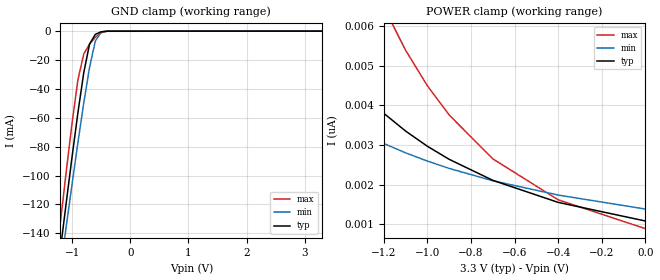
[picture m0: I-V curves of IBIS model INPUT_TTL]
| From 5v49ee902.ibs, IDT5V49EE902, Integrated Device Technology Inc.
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|   Model INPUT_TTL
[Model]   INPUT_TTL
Model_type   Input
Polarity   Non-Inverting
Vinl =  0.80000V
Vinh =  2.00000V
C_comp   3.15000pF   3.15000pF   3.15000pF
[Temperature Range]   25.00000   100.00000   -40.00000
[Voltage Range]   3.30000V   3.00000V   3.60000V
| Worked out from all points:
|   GND clamp passes 1 mA (typ) near -0.53 V on its own axis
[GND_clamp]
| voltage   I(typ)   I(min)   I(max)
-3.3V     -860.5mA   -813.9mA   -910.1mA
-1.3V     -183.6mA   -194.8mA   -167.8mA
-1.2V     -150.9mA   -164.8mA   -132.1mA
-1.1V     -118.6mA   -135.1mA   -97.13mA
-1V       -86.99mA   -105.9mA   -63.61mA
-900mV    -56.64mA   -77.31mA   -33.82mA
-800mV    -29.01mA   -50mA      -15.89mA
-700mV    -9.031mA   -25.22mA   -9.146mA
-600mV    -2.261mA   -6.881mA   -4.277mA
-500mV    -493.9uA   -650.7uA   -1.144mA
-400mV    -59.34uA   -43.85uA   -131.5uA
3.3V      1.08nA     1.636nA    591.5pA
[POWER_clamp]
| voltage   I(typ)   I(min)   I(max)
-3.3V     74.3nA     29.42nA    315.2nA
-1.9V     9.867nA    5.868nA    24.24nA
-1.6V     6.467nA    4.338nA    13.72nA
-1.5V     5.639nA    3.947nA    11.36nA
-1.4V     4.929nA    3.604nA    9.41nA
-1.2V     3.799nA    3.036nA    6.48nA
-1.1V     3.351nA    2.801nA    5.39nA
-1V       2.967nA    2.593nA    4.494nA
-900mV    2.637nA    2.408nA    3.756nA
-700mV    2.107nA    2.096nA    2.649nA
-400mV    1.55nA     1.735nA    1.615nA
0V        1.08nA     1.382nA    886.8pA
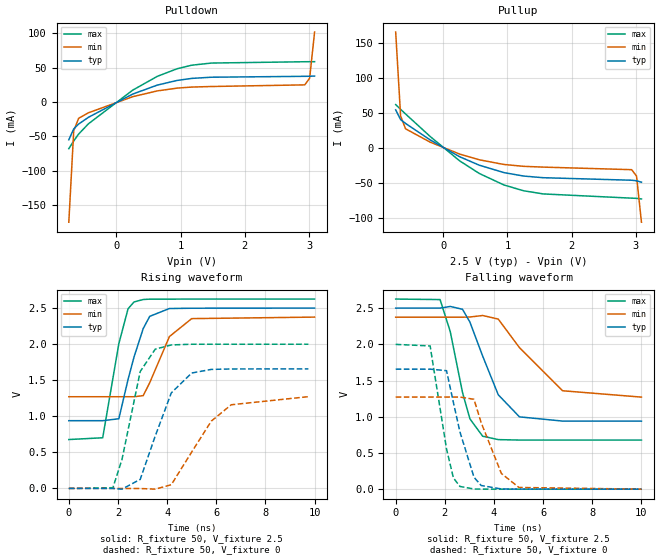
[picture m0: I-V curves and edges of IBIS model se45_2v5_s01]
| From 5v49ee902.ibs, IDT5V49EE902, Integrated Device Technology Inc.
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[Model]   se45_2v5_s01
Model_type   Output
Polarity   Non-Inverting
|   typ   min   max
C_comp   2pF   1.5pF   2.5pF
Vmeas = 1.25V
Rref = 50
Cref = 0
Vref = 1.25V
|   typ   min   max
[Voltage range]   2.5V   2.375V   2.625V
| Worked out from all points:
|   slope of the pulldown table from 0 to 0.375 V, typ, clamps not added: 23.2 ohm
|   slope of the pullup table from 0 to 0.375 V, typ, clamps not added: 21 ohm
|   rising waveform, R_fixture 50, V_fixture 2.5: 20-80 % time 748ps typ, 875ps min, 623ps max; typ from 0.939 V to 2.5 V
|   falling waveform, R_fixture 50, V_fixture 2.5: 20-80 % time 1.1ns typ, 1.47ns min, 751ps max; typ from 2.5 V to 0.939 V
|   rising waveform, R_fixture 50, V_fixture 0: 20-80 % time 1.03ns typ, 1.46ns min, 725ps max; typ from 0 V to 1.66 V
|   falling waveform, R_fixture 50, V_fixture 0: 20-80 % time 712ps typ, 832ps min, 579ps max; typ from 1.66 V to 0 V
[Pulldown]
|Voltage   I (typ)   I (min)   I (max)
|Note, modeling breaks down at 250mA and above.  This is well beyond the functional   |
|operating range of the device.  Should this scenario occur, catastrophic failure and   |
|possible damage to the device and/or board is of higher concern than the I-V curve   |
|behavior.  The IBIS checker will flag currents in excess of 10A with warnings.  Lines   |
|with currents in excess of 0.35 A have been commented out.  The points still remain|
|available to the user if the user desires to use them.   |
|-2.50000e+00   -4.54709e+01   -3.63694e+01   -6.07959e+01
|-2.42347e+00   -4.32502e+01   -3.46594e+01   -5.77053e+01
|-2.34694e+00   -4.10314e+01   -3.29511e+01   -5.46170e+01
|-2.27041e+00   -3.88148e+01   -3.12446e+01   -5.15313e+01
|-2.19388e+00   -3.66007e+01   -2.95401e+01   -4.84486e+01
|-2.11735e+00   -3.43893e+01   -2.78380e+01   -4.53691e+01
|-2.04082e+00   -3.21809e+01   -2.61384e+01   -4.22934e+01
|-1.96429e+00   -2.99761e+01   -2.44418e+01   -3.92219e+01
|-1.88776e+00   -2.77753e+01   -2.27484e+01   -3.61555e+01
|-1.81122e+00   -2.55791e+01   -2.10589e+01   -3.30948e+01
|-1.73469e+00   -2.33884e+01   -1.93737e+01   -3.00411e+01
|-1.65816e+00   -2.12042e+01   -1.76937e+01   -2.69958e+01
|-1.58163e+00   -1.90279e+01   -1.60198e+01   -2.39607e+01
|-1.50510e+00   -1.68611e+01   -1.43533e+01   -2.09385e+01
|-1.42857e+00   -1.47065e+01   -1.26960e+01   -1.79331e+01
|-1.35204e+00   -1.25675e+01   -1.10500e+01   -1.49501e+01
|-1.27551e+00   -1.04495e+01   -9.41889e+00   -1.19989e+01
|-1.19898e+00   -8.36102e+00   -7.80755e+00   -9.09553e+00
|-1.12245e+00   -6.31683e+00   -6.22400e+00   -6.27207e+00
|-1.04592e+00   -4.34540e+00   -4.68188e+00   -3.60463e+00
|-9.69388e-01   -2.51112e+00   -3.20700e+00   -1.33260e+00
|-8.92857e-01   -9.89892e-01   -1.85502e+00   -2.01598e-01
|-8.16327e-01   -1.92135e-01   -7.61074e-01   -8.24374e-02
-739.8mV  -54.82mA   -174.4mA   -67.73mA
-663.3mV  -39mA      -41.68mA   -56.5mA
-586.7mV  -31.96mA   -23.62mA   -46.47mA
-433.7mV  -22.15mA   -15.6mA    -31.55mA
255.1mV   11.54mA    7.746mA    17.23mA
637.8mV   24.55mA    16.14mA    37.26mA
943.9mV   31.29mA    20.16mA    48.22mA
1.173V    34.28mA    21.72mA    53.44mA
1.48V     36mA       22.52mA    56.56mA
2.934V    37.31mA    24.91mA    58.47mA
3.01V     37.39mA    34.58mA    58.51mA
3.087V    37.69mA    101.5mA    58.57mA
| 3.16327e+00   3.94370e-02   3.90716e-01   5.87161e-02
| 3.23980e+00   5.34569e-02   9.26332e-01   5.92247e-02
| 3.31633e+00   1.87777e-01   1.58664e+00   6.05142e-02
| 3.39286e+00   7.03900e-01   2.30650e+00   6.31621e-02
| 3.46939e+00   1.49296e+00   3.05902e+00   8.17834e-02
| 3.54592e+00   2.39302e+00   3.83167e+00   3.62573e-01
| 3.62245e+00   3.34512e+00   4.61786e+00   1.23067e+00
| 3.69898e+00   4.32630e+00   5.41369e+00   2.35283e+00
| 3.77551e+00   5.32579e+00   6.21672e+00   3.56536e+00
| 3.85204e+00   6.33779e+00   7.02533e+00   4.82080e+00
| 3.92857e+00   7.35883e+00   7.83838e+00   6.10084e+00
| 4.00510e+00   8.38670e+00   8.65504e+00   7.39669e+00
| 4.08163e+00   9.41993e+00   9.47469e+00   8.70352e+00
| 4.15816e+00   1.04574e+01   1.02969e+01   1.00184e+01
| 4.23469e+00   1.14984e+01   1.11212e+01   1.13394e+01
| 4.31122e+00   1.25424e+01   1.19474e+01   1.26653e+01
| 4.38776e+00   1.35888e+01   1.27751e+01   1.39952e+01
| 4.46429e+00   1.46373e+01   1.36044e+01   1.53282e+01
| 4.54082e+00   1.56877e+01   1.44348e+01   1.66640e+01
| 4.61735e+00   1.67397e+01   1.52665e+01   1.80021e+01
| 4.69388e+00   1.77932e+01   1.60991e+01   1.93422e+01
| 4.77041e+00   1.88479e+01   1.69326e+01   2.06841e+01
| 4.84694e+00   1.99037e+01   1.77670e+01   2.20275e+01
| 4.92347e+00   2.09606e+01   1.86021e+01   2.33723e+01
| 5.00000e+00   2.20184e+01   1.94379e+01   2.47183e+01
[Pullup]
|Voltage   I (typ)   I (min)   I (max)
|Note, modeling breaks down at 250mA and above.  This is well beyond the functional   |
|operating range of the device.  Should this scenario occur, catastrophic failure and   |
|possible damage to the device and/or board is of higher concern than the I-V curve   |
|behavior.  The IBIS checker will flag currents in excess of 10A with warnings.  Lines   |
|with currents in excess of 0.35 A have been commented out.  The points still remain|
|available to the user if the user desires to use them.   |
|-2.50000e+00   2.19765e+01   1.80472e+01   2.68517e+01
|-2.42347e+00   2.09191e+01   1.72127e+01   2.55048e+01
|-2.34694e+00   1.98626e+01   1.63791e+01   2.41589e+01
|-2.27041e+00   1.88071e+01   1.55463e+01   2.28141e+01
|-2.19388e+00   1.77528e+01   1.47145e+01   2.14705e+01
|-2.11735e+00   1.66997e+01   1.38838e+01   2.01283e+01
|-2.04082e+00   1.56480e+01   1.30543e+01   1.87877e+01
|-1.96429e+00   1.45980e+01   1.22261e+01   1.74489e+01
|-1.88776e+00   1.35497e+01   1.13995e+01   1.61122e+01
|-1.81122e+00   1.25036e+01   1.05747e+01   1.47780e+01
|-1.73469e+00   1.14600e+01   9.75186e+00   1.34466e+01
|-1.65816e+00   1.04193e+01   8.93142e+00   1.21187e+01
|-1.58163e+00   9.38215e+00   8.11380e+00   1.07950e+01
|-1.50510e+00   8.34928e+00   7.29955e+00   9.47668e+00
|-1.42857e+00   7.32178e+00   6.48942e+00   8.16516e+00
|-1.35204e+00   6.30119e+00   5.68442e+00   6.86272e+00
|-1.27551e+00   5.28973e+00   4.88602e+00   5.57292e+00
|-1.19898e+00   4.29091e+00   4.09630e+00   4.30185e+00
|-1.12245e+00   3.31066e+00   3.31857e+00   3.06117e+00
|-1.04592e+00   2.36002e+00   2.55827e+00   1.87712e+00
|-9.69388e-01   1.46263e+00   1.82537e+00   8.26238e-01
|-8.92857e-01   6.79721e-01   1.14025e+00   1.77022e-01
|-8.16327e-01   1.78304e-01   5.50947e-01   7.20287e-02
-739.8mV  54.64mA    166.3mA    62.19mA
-663.3mV  40.61mA    45.96mA    55.4mA
-586.7mV  35.13mA    27.42mA    48.78mA
-204.1mV  11.53mA    8.292mA    16.47mA
255.1mV   -12.67mA   -8.857mA   -18.54mA
561.2mV   -24.84mA   -17.08mA   -36.7mA
943.9mV   -35.45mA   -23.78mA   -53.18mA
1.25V     -40.42mA   -26.48mA   -61.53mA
1.556V    -42.81mA   -27.59mA   -66.09mA
2.934V    -46.44mA   -31.28mA   -72.19mA
3.01V     -47.21mA   -40.39mA   -72.48mA
3.087V    -49.28mA   -106.7mA   -73.28mA
| 3.16327e+00   -5.35776e-02   -4.94236e-01   -7.58575e-02
| 3.23980e+00   -6.85824e-02   -1.43626e+00   -8.09811e-02
| 3.31633e+00   -2.12479e-01   -2.71822e+00   -8.81300e-02
| 3.39286e+00   -1.02359e+00   -4.15794e+00   -9.69442e-02
| 3.46939e+00   -2.55073e+00   -5.67974e+00   -1.18777e-01
| 3.54592e+00   -4.38708e+00   -7.25021e+00   -4.69271e-01
| 3.62245e+00   -6.35927e+00   -8.85247e+00   -2.14689e+00
| 3.69898e+00   -8.40369e+00   -1.04769e+01   -4.62063e+00
| 3.77551e+00   -1.04921e+01   -1.21177e+01   -7.36117e+00
| 3.85204e+00   -1.26099e+01   -1.37710e+01   -1.02197e+01
| 3.92857e+00   -1.47486e+01   -1.54342e+01   -1.31429e+01
| 4.00510e+00   -1.69029e+01   -1.71053e+01   -1.61066e+01
| 4.08163e+00   -1.90692e+01   -1.87829e+01   -1.90980e+01
| 4.15816e+00   -2.12452e+01   -2.04660e+01   -2.21093e+01
| 4.23469e+00   -2.34289e+01   -2.21537e+01   -2.51357e+01
| 4.31122e+00   -2.56192e+01   -2.38455e+01   -2.81738e+01
| 4.38776e+00   -2.78148e+01   -2.55407e+01   -3.12215e+01
| 4.46429e+00   -3.00151e+01   -2.72389e+01   -3.42769e+01
| 4.54082e+00   -3.22195e+01   -2.89399e+01   -3.73388e+01
| 4.61735e+00   -3.44273e+01   -3.06432e+01   -4.04061e+01
| 4.69388e+00   -3.66382e+01   -3.23486e+01   -4.34782e+01
| 4.77041e+00   -3.88519e+01   -3.40560e+01   -4.65543e+01
| 4.84694e+00   -4.10679e+01   -3.57652e+01   -4.96340e+01
| 4.92347e+00   -4.32862e+01   -3.74759e+01   -5.27168e+01
| 5.00000e+00   -4.55064e+01   -3.91880e+01   -5.58024e+01
[Ramp]
|   typ   min   max
dV/dt_r   0.936/0.747n   0.662/0.874n   1.168/0.623n
dV/dt_f   0.951/1.109n   0.676/1.496n   1.186/0.762n
R_load =   50
[Rising Waveform]
R_fixture = 50
V_fixture = 2.5   |Vcc_typ
V_fixture_min = 2.375 |Vcc_min
V_fixture_max = 2.625 |Vcc_max
C_fixture = 0.0p
| Time   typ   min   max
0s        939.3mV    1.271V     677.7mV
1.379ns   939.3mV    1.271V     702.4mV
2.035ns   965.7mV    1.271V     2.006V
2.411ns   1.511V     1.271V     2.491V
2.654ns   1.823V     1.271V     2.585V
3.027ns   2.216V     1.286V     2.619V
3.293ns   2.386V     1.466V     2.624V
4.095ns   2.494V     2.106V     2.624V
5ns       2.498V     2.354V     2.625V
10ns      2.5V       2.375V     2.625V
[Falling Waveform]
R_fixture = 50
V_fixture = 2.5   |Vcc_typ
V_fixture_min = 2.375 |Vcc_min
V_fixture_max = 2.625 |Vcc_max
C_fixture = 0.0p
| Time   typ   min   max
0s        2.5V       2.375V     2.625V
1.806ns   2.5V       2.375V     2.618V
2.22ns    2.523V     2.375V     2.176V
2.718ns   2.484V     2.375V     1.336V
3.019ns   2.308V     2.377V     971.7mV
3.538ns   1.839V     2.398V     731.3mV
4.172ns   1.304V     2.349V     684.3mV
5.036ns   998.4mV    1.954V     678.1mV
6.789ns   940.3mV    1.359V     677.8mV
10ns      939.4mV    1.271V     677.8mV
[Rising Waveform]
R_fixture = 50
V_fixture = 0
C_fixture = 0.0p
| Time   typ   min   max
0s        96.64nV    102.5nV    85.59nV
1.795ns   -48.57uV   108.9nV    10.23mV
2.163ns   -10.07mV   7.207nV    401.4mV
2.905ns   125.5mV    -1.052mV   1.621V
3.518ns   727.9mV    -10.15mV   1.931V
4.171ns   1.325V     52.09mV    1.989V
5ns       1.6V       504.9mV    1.999V
5.799ns   1.65V      933.5mV    1.999V
6.608ns   1.656V     1.16V      1.999V
9.748ns   1.657V     1.272V     1.999V
[Falling Waveform]
R_fixture = 50
V_fixture = 0
C_fixture = 0.0p
| Time   typ   min   max
0s        1.657V     1.272V     1.999V
1.401ns   1.657V     1.272V     1.978V
2.069ns   1.636V     1.272V     554.6mV
2.348ns   1.197V     1.272V     155.5mV
2.614ns   790.9mV    1.272V     37.82mV
3.185ns   165.4mV    1.241V     2.015mV
3.478ns   50.48mV    918.2mV    1.131mV
4.3ns     2.689mV    217.2mV    261.2uV
5.013ns   752.7uV    23.58mV    110.6uV
10ns      69.28uV    129.6uV    37.48uV
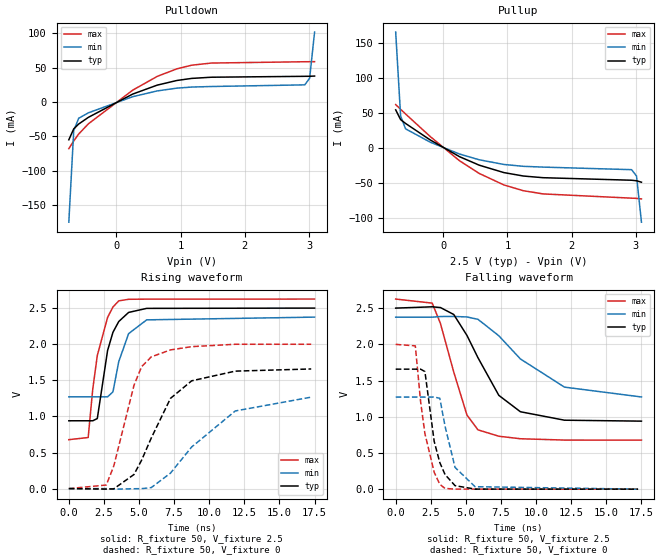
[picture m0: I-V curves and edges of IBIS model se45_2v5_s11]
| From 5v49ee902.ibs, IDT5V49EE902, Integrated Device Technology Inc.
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[Model]   se45_2v5_s11
Model_type   Output
Polarity   Non-Inverting
|   typ   min   max
C_comp   2pF   1.5pF   2.5pF
Vmeas = 1.25V
Rref = 50
Cref = 0
Vref = 1.25V
|   typ   min   max
[Voltage range]   2.5V   2.375V   2.625V
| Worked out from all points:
|   slope of the pulldown table from 0 to 0.375 V, typ, clamps not added: 23.2 ohm
|   slope of the pullup table from 0 to 0.375 V, typ, clamps not added: 21 ohm
|   rising waveform, R_fixture 50, V_fixture 2.5: 20-80 % time 963ps typ, 986ps min, 954ps max; typ from 0.939 V to 2.5 V
|   falling waveform, R_fixture 50, V_fixture 2.5: 20-80 % time 2.63ns typ, 3.79ns min, 1.72ns max; typ from 2.5 V to 0.939 V
|   rising waveform, R_fixture 50, V_fixture 0: 20-80 % time 2.5ns typ, 3.77ns min, 1.64ns max; typ from 0 V to 1.66 V
|   falling waveform, R_fixture 50, V_fixture 0: 20-80 % time 935ps typ, 945ps min, 910ps max; typ from 1.66 V to 0 V
[Pulldown]
|Voltage   I (typ)   I (min)   I (max)
|Note, modeling breaks down at 250mA and above.  This is well beyond the functional   |
|operating range of the device.  Should this scenario occur, catastrophic failure and   |
|possible damage to the device and/or board is of higher concern than the I-V curve   |
|behavior.  The IBIS checker will flag currents in excess of 10A with warnings.  Lines   |
|with currents in excess of 0.35 A have been commented out.  The points still remain|
|available to the user if the user desires to use them.   |
|-2.50000e+00   -4.54709e+01   -3.63694e+01   -6.07959e+01
|-2.42347e+00   -4.32502e+01   -3.46594e+01   -5.77053e+01
|-2.34694e+00   -4.10314e+01   -3.29511e+01   -5.46170e+01
|-2.27041e+00   -3.88148e+01   -3.12446e+01   -5.15313e+01
|-2.19388e+00   -3.66007e+01   -2.95401e+01   -4.84486e+01
|-2.11735e+00   -3.43893e+01   -2.78380e+01   -4.53691e+01
|-2.04082e+00   -3.21809e+01   -2.61384e+01   -4.22934e+01
|-1.96429e+00   -2.99761e+01   -2.44418e+01   -3.92219e+01
|-1.88776e+00   -2.77753e+01   -2.27484e+01   -3.61555e+01
|-1.81122e+00   -2.55791e+01   -2.10589e+01   -3.30948e+01
|-1.73469e+00   -2.33884e+01   -1.93737e+01   -3.00411e+01
|-1.65816e+00   -2.12042e+01   -1.76937e+01   -2.69958e+01
|-1.58163e+00   -1.90279e+01   -1.60198e+01   -2.39607e+01
|-1.50510e+00   -1.68611e+01   -1.43533e+01   -2.09385e+01
|-1.42857e+00   -1.47065e+01   -1.26960e+01   -1.79331e+01
|-1.35204e+00   -1.25675e+01   -1.10500e+01   -1.49501e+01
|-1.27551e+00   -1.04495e+01   -9.41889e+00   -1.19989e+01
|-1.19898e+00   -8.36102e+00   -7.80755e+00   -9.09553e+00
|-1.12245e+00   -6.31683e+00   -6.22400e+00   -6.27207e+00
|-1.04592e+00   -4.34540e+00   -4.68188e+00   -3.60463e+00
|-9.69388e-01   -2.51112e+00   -3.20700e+00   -1.33260e+00
|-8.92857e-01   -9.89892e-01   -1.85502e+00   -2.01598e-01
|-8.16327e-01   -1.92135e-01   -7.61074e-01   -8.24374e-02
-739.8mV  -54.82mA   -174.4mA   -67.73mA
-663.3mV  -39mA      -41.68mA   -56.5mA
-586.7mV  -31.96mA   -23.62mA   -46.47mA
-433.7mV  -22.15mA   -15.6mA    -31.55mA
255.1mV   11.54mA    7.746mA    17.23mA
637.8mV   24.55mA    16.14mA    37.26mA
943.9mV   31.29mA    20.16mA    48.22mA
1.173V    34.28mA    21.72mA    53.44mA
1.48V     36mA       22.52mA    56.56mA
2.934V    37.31mA    24.91mA    58.47mA
3.01V     37.39mA    34.58mA    58.51mA
3.087V    37.69mA    101.5mA    58.57mA
| 3.16327e+00   3.94370e-02   3.90716e-01   5.87161e-02
| 3.23980e+00   5.34569e-02   9.26332e-01   5.92247e-02
| 3.31633e+00   1.87777e-01   1.58664e+00   6.05142e-02
| 3.39286e+00   7.03900e-01   2.30650e+00   6.31621e-02
| 3.46939e+00   1.49296e+00   3.05902e+00   8.17834e-02
| 3.54592e+00   2.39302e+00   3.83167e+00   3.62573e-01
| 3.62245e+00   3.34512e+00   4.61786e+00   1.23067e+00
| 3.69898e+00   4.32630e+00   5.41369e+00   2.35283e+00
| 3.77551e+00   5.32579e+00   6.21672e+00   3.56536e+00
| 3.85204e+00   6.33779e+00   7.02533e+00   4.82080e+00
| 3.92857e+00   7.35883e+00   7.83838e+00   6.10084e+00
| 4.00510e+00   8.38670e+00   8.65504e+00   7.39669e+00
| 4.08163e+00   9.41993e+00   9.47469e+00   8.70352e+00
| 4.15816e+00   1.04574e+01   1.02969e+01   1.00184e+01
| 4.23469e+00   1.14984e+01   1.11212e+01   1.13394e+01
| 4.31122e+00   1.25424e+01   1.19474e+01   1.26653e+01
| 4.38776e+00   1.35888e+01   1.27751e+01   1.39952e+01
| 4.46429e+00   1.46373e+01   1.36044e+01   1.53282e+01
| 4.54082e+00   1.56877e+01   1.44348e+01   1.66640e+01
| 4.61735e+00   1.67397e+01   1.52665e+01   1.80021e+01
| 4.69388e+00   1.77932e+01   1.60991e+01   1.93422e+01
| 4.77041e+00   1.88479e+01   1.69326e+01   2.06841e+01
| 4.84694e+00   1.99037e+01   1.77670e+01   2.20275e+01
| 4.92347e+00   2.09606e+01   1.86021e+01   2.33723e+01
| 5.00000e+00   2.20184e+01   1.94379e+01   2.47183e+01
[Pullup]
|Voltage   I (typ)   I (min)   I (max)
|Note, modeling breaks down at 250mA and above.  This is well beyond the functional   |
|operating range of the device.  Should this scenario occur, catastrophic failure and   |
|possible damage to the device and/or board is of higher concern than the I-V curve   |
|behavior.  The IBIS checker will flag currents in excess of 10A with warnings.  Lines   |
|with currents in excess of 0.35 A have been commented out.  The points still remain|
|available to the user if the user desires to use them.   |
|-2.50000e+00   2.19765e+01   1.80472e+01   2.68517e+01
|-2.42347e+00   2.09191e+01   1.72127e+01   2.55048e+01
|-2.34694e+00   1.98626e+01   1.63791e+01   2.41589e+01
|-2.27041e+00   1.88071e+01   1.55463e+01   2.28141e+01
|-2.19388e+00   1.77528e+01   1.47145e+01   2.14705e+01
|-2.11735e+00   1.66997e+01   1.38838e+01   2.01283e+01
|-2.04082e+00   1.56480e+01   1.30543e+01   1.87877e+01
|-1.96429e+00   1.45980e+01   1.22261e+01   1.74489e+01
|-1.88776e+00   1.35497e+01   1.13995e+01   1.61122e+01
|-1.81122e+00   1.25036e+01   1.05747e+01   1.47780e+01
|-1.73469e+00   1.14600e+01   9.75186e+00   1.34466e+01
|-1.65816e+00   1.04193e+01   8.93142e+00   1.21187e+01
|-1.58163e+00   9.38215e+00   8.11380e+00   1.07950e+01
|-1.50510e+00   8.34928e+00   7.29955e+00   9.47668e+00
|-1.42857e+00   7.32178e+00   6.48942e+00   8.16516e+00
|-1.35204e+00   6.30119e+00   5.68442e+00   6.86272e+00
|-1.27551e+00   5.28973e+00   4.88602e+00   5.57292e+00
|-1.19898e+00   4.29091e+00   4.09630e+00   4.30185e+00
|-1.12245e+00   3.31066e+00   3.31857e+00   3.06117e+00
|-1.04592e+00   2.36002e+00   2.55827e+00   1.87712e+00
|-9.69388e-01   1.46263e+00   1.82537e+00   8.26238e-01
|-8.92857e-01   6.79721e-01   1.14025e+00   1.77022e-01
|-8.16327e-01   1.78304e-01   5.50947e-01   7.20287e-02
-739.8mV  54.64mA    166.3mA    62.19mA
-663.3mV  40.61mA    45.96mA    55.4mA
-586.7mV  35.13mA    27.42mA    48.78mA
-204.1mV  11.53mA    8.292mA    16.47mA
255.1mV   -12.67mA   -8.857mA   -18.54mA
561.2mV   -24.84mA   -17.08mA   -36.7mA
943.9mV   -35.45mA   -23.78mA   -53.18mA
1.25V     -40.42mA   -26.48mA   -61.53mA
1.556V    -42.81mA   -27.59mA   -66.09mA
2.934V    -46.44mA   -31.28mA   -72.19mA
3.01V     -47.21mA   -40.39mA   -72.48mA
3.087V    -49.28mA   -106.7mA   -73.28mA
| 3.16327e+00   -5.35776e-02   -4.94236e-01   -7.58575e-02
| 3.23980e+00   -6.85824e-02   -1.43626e+00   -8.09811e-02
| 3.31633e+00   -2.12479e-01   -2.71822e+00   -8.81300e-02
| 3.39286e+00   -1.02359e+00   -4.15794e+00   -9.69442e-02
| 3.46939e+00   -2.55073e+00   -5.67974e+00   -1.18777e-01
| 3.54592e+00   -4.38708e+00   -7.25021e+00   -4.69271e-01
| 3.62245e+00   -6.35927e+00   -8.85247e+00   -2.14689e+00
| 3.69898e+00   -8.40369e+00   -1.04769e+01   -4.62063e+00
| 3.77551e+00   -1.04921e+01   -1.21177e+01   -7.36117e+00
| 3.85204e+00   -1.26099e+01   -1.37710e+01   -1.02197e+01
| 3.92857e+00   -1.47486e+01   -1.54342e+01   -1.31429e+01
| 4.00510e+00   -1.69029e+01   -1.71053e+01   -1.61066e+01
| 4.08163e+00   -1.90692e+01   -1.87829e+01   -1.90980e+01
| 4.15816e+00   -2.12452e+01   -2.04660e+01   -2.21093e+01
| 4.23469e+00   -2.34289e+01   -2.21537e+01   -2.51357e+01
| 4.31122e+00   -2.56192e+01   -2.38455e+01   -2.81738e+01
| 4.38776e+00   -2.78148e+01   -2.55407e+01   -3.12215e+01
| 4.46429e+00   -3.00151e+01   -2.72389e+01   -3.42769e+01
| 4.54082e+00   -3.22195e+01   -2.89399e+01   -3.73388e+01
| 4.61735e+00   -3.44273e+01   -3.06432e+01   -4.04061e+01
| 4.69388e+00   -3.66382e+01   -3.23486e+01   -4.34782e+01
| 4.77041e+00   -3.88519e+01   -3.40560e+01   -4.65543e+01
| 4.84694e+00   -4.10679e+01   -3.57652e+01   -4.96340e+01
| 4.92347e+00   -4.32862e+01   -3.74759e+01   -5.27168e+01
| 5.00000e+00   -4.55064e+01   -3.91880e+01   -5.58024e+01
[Ramp]
|   typ   min   max
dV/dt_r   0.936/0.963n   0.662/0.986n   1.168/0.953n
dV/dt_f   0.951/2.67n  0.675/3.841n   1.186/1.745n
R_load =   50
[Rising Waveform]
R_fixture = 50
V_fixture = 2.5   |Vcc_typ
V_fixture_min = 2.375 |Vcc_min
V_fixture_max = 2.625 |Vcc_max
C_fixture = 0.0p
| Time   typ   min   max
0s        939.3mV    1.271V     677.7mV
1.379ns   939.3mV    1.271V     707.5mV
1.705ns   939.3mV    1.271V     1.379V
2.029ns   970.5mV    1.271V     1.844V
2.76ns    1.912V     1.271V     2.37V
3.143ns   2.165V     1.34V      2.515V
3.556ns   2.314V     1.759V     2.6V
4.258ns   2.44V      2.146V     2.622V
5.544ns   2.496V     2.337V     2.624V
17.5ns    2.5V       2.375V     2.625V
[Falling Waveform]
R_fixture = 50
V_fixture = 2.5   |Vcc_typ
V_fixture_min = 2.375 |Vcc_min
V_fixture_max = 2.625 |Vcc_max
C_fixture = 0.0p
| Time   typ   min   max
0s        2.5V       2.375V     2.625V
2.6ns     2.518V     2.375V     2.569V
3.186ns   2.508V     2.384V     2.288V
4.133ns   2.412V     2.385V     1.618V
5.074ns   2.123V     2.378V     1.023V
5.861ns   1.814V     2.345V     818.9mV
7.345ns   1.295V     2.118V     730.9mV
8.881ns   1.069V     1.798V     696.2mV
12.02ns   952.3mV    1.409V     677.9mV
17.5ns    939.3mV    1.273V     677.7mV
[Rising Waveform]
R_fixture = 50
V_fixture = 0
C_fixture = 0.0p
| Time   typ   min   max
0s        96.64nV    102.5nV    85.59nV
2.668ns   -7.256mV   32.44uV    49.65mV
3.199ns   -3.215mV   -7.738mV   311.5mV
4.638ns   195.2mV    -1.95mV    1.429V
5.18ns    392.6mV    -822.5uV   1.688V
5.875ns   702.1mV    14.3mV     1.825V
7.241ns   1.25V      215mV      1.921V
8.75ns    1.493V     576.9mV    1.966V
11.85ns   1.627V     1.075V     1.999V
17.26ns   1.657V     1.267V     1.999V
[Falling Waveform]
R_fixture = 50
V_fixture = 0
C_fixture = 0.0p
| Time   typ   min   max
0s        1.657V     1.272V     1.999V
1.397ns   1.657V     1.272V     1.979V
1.774ns   1.657V     1.272V     1.208V
2.081ns   1.624V     1.272V     767.4mV
2.742ns   659mV      1.272V     232.8mV
3.141ns   367.5mV    1.255V     66.94mV
3.515ns   201.4mV    868.7mV    9.915mV
4.227ns   48.27mV    300.1mV    1.079mV
5.65ns    1.231mV    34.22mV    461.5uV
17.26ns   31.51uV    67.45uV    18.41uV
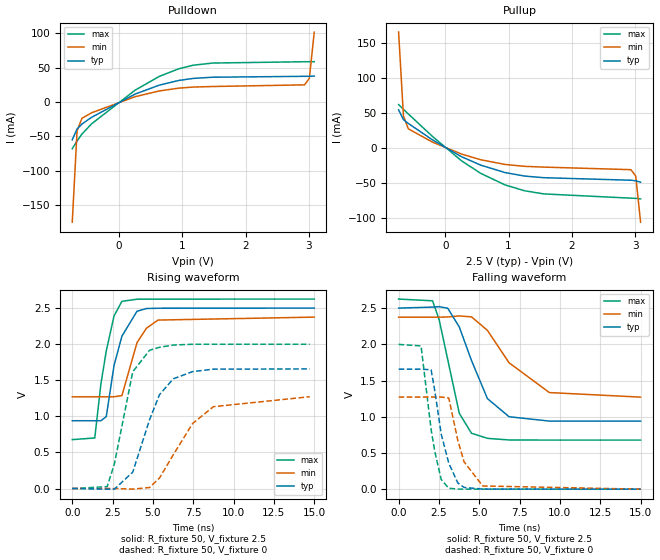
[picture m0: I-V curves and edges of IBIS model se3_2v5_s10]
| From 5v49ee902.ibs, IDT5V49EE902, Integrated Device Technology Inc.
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[Model]   se3_2v5_s10
Model_type   Output
Polarity   Non-Inverting
|   typ   min   max
C_comp   2pF   1.5pF   2.5pF
Vmeas = 1.25V
Rref = 50
Cref = 0
Vref = 1.25V
|   typ   min   max
[Voltage range]   2.5V   2.375V   2.625V
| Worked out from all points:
|   slope of the pulldown table from 0 to 0.375 V, typ, clamps not added: 23.2 ohm
|   slope of the pullup table from 0 to 0.375 V, typ, clamps not added: 21 ohm
|   rising waveform, R_fixture 50, V_fixture 2.5: 20-80 % time 951ps typ, 993ps min, 848ps max; typ from 0.939 V to 2.5 V
|   falling waveform, R_fixture 50, V_fixture 2.5: 20-80 % time 1.64ns typ, 2.29ns min, 1.11ns max; typ from 2.5 V to 0.939 V
|   rising waveform, R_fixture 50, V_fixture 0: 20-80 % time 1.55ns typ, 2.25ns min, 1.06ns max; typ from 0 V to 1.66 V
|   falling waveform, R_fixture 50, V_fixture 0: 20-80 % time 888ps typ, 940ps min, 786ps max; typ from 1.66 V to 0 V
[Pulldown]
|Voltage   I (typ)   I (min)   I (max)
|Note, modeling breaks down at 250mA and above.  This is well beyond the functional   |
|operating range of the device.  Should this scenario occur, catastrophic failure and   |
|possible damage to the device and/or board is of higher concern than the I-V curve   |
|behavior.  The IBIS checker will flag currents in excess of 10A with warnings.  Lines   |
|with currents in excess of 0.35 A have been commented out.  The points still remain|
|available to the user if the user desires to use them.   |
|-2.50000e+00   -4.54709e+01   -3.63694e+01   -6.07959e+01
|-2.42347e+00   -4.32502e+01   -3.46594e+01   -5.77053e+01
|-2.34694e+00   -4.10314e+01   -3.29511e+01   -5.46170e+01
|-2.27041e+00   -3.88148e+01   -3.12446e+01   -5.15313e+01
|-2.19388e+00   -3.66007e+01   -2.95401e+01   -4.84486e+01
|-2.11735e+00   -3.43893e+01   -2.78380e+01   -4.53691e+01
|-2.04082e+00   -3.21809e+01   -2.61384e+01   -4.22934e+01
|-1.96429e+00   -2.99761e+01   -2.44418e+01   -3.92219e+01
|-1.88776e+00   -2.77753e+01   -2.27484e+01   -3.61555e+01
|-1.81122e+00   -2.55791e+01   -2.10589e+01   -3.30948e+01
|-1.73469e+00   -2.33884e+01   -1.93737e+01   -3.00411e+01
|-1.65816e+00   -2.12042e+01   -1.76937e+01   -2.69958e+01
|-1.58163e+00   -1.90279e+01   -1.60198e+01   -2.39607e+01
|-1.50510e+00   -1.68611e+01   -1.43533e+01   -2.09385e+01
|-1.42857e+00   -1.47065e+01   -1.26960e+01   -1.79331e+01
|-1.35204e+00   -1.25675e+01   -1.10500e+01   -1.49501e+01
|-1.27551e+00   -1.04495e+01   -9.41889e+00   -1.19989e+01
|-1.19898e+00   -8.36102e+00   -7.80755e+00   -9.09553e+00
|-1.12245e+00   -6.31683e+00   -6.22400e+00   -6.27207e+00
|-1.04592e+00   -4.34540e+00   -4.68188e+00   -3.60463e+00
|-9.69388e-01   -2.51112e+00   -3.20700e+00   -1.33260e+00
|-8.92857e-01   -9.89892e-01   -1.85502e+00   -2.01598e-01
|-8.16327e-01   -1.92135e-01   -7.61074e-01   -8.24374e-02
-739.8mV  -54.82mA   -174.4mA   -67.73mA
-663.3mV  -39mA      -41.68mA   -56.5mA
-586.7mV  -31.96mA   -23.62mA   -46.47mA
-433.7mV  -22.15mA   -15.6mA    -31.55mA
255.1mV   11.54mA    7.746mA    17.23mA
637.8mV   24.55mA    16.14mA    37.26mA
943.9mV   31.29mA    20.16mA    48.22mA
1.173V    34.28mA    21.72mA    53.44mA
1.48V     36mA       22.52mA    56.56mA
2.934V    37.31mA    24.91mA    58.47mA
3.01V     37.39mA    34.58mA    58.51mA
3.087V    37.69mA    101.5mA    58.57mA
| 3.16327e+00   3.94370e-02   3.90706e-01   5.87161e-02
| 3.23980e+00   5.34568e-02   9.26296e-01   5.92247e-02
| 3.31633e+00   1.87774e-01   1.58657e+00   6.05142e-02
| 3.39286e+00   7.03870e-01   2.30639e+00   6.31621e-02
| 3.46939e+00   1.49288e+00   3.05886e+00   8.17834e-02
| 3.54592e+00   2.39288e+00   3.83148e+00   3.62561e-01
| 3.62245e+00   3.34491e+00   4.61762e+00   1.23059e+00
| 3.69898e+00   4.32602e+00   5.41341e+00   2.35266e+00
| 3.77551e+00   5.32544e+00   6.21640e+00   3.56507e+00
| 3.85204e+00   6.33737e+00   7.02496e+00   4.82041e+00
| 3.92857e+00   7.35834e+00   7.83797e+00   6.10033e+00
| 4.00510e+00   8.38614e+00   8.65458e+00   7.39607e+00
| 4.08163e+00   9.41929e+00   9.47419e+00   8.70278e+00
| 4.15816e+00   1.04567e+01   1.02963e+01   1.00176e+01
| 4.23469e+00   1.14977e+01   1.11206e+01   1.13385e+01
| 4.31122e+00   1.25415e+01   1.19467e+01   1.26642e+01
| 4.38776e+00   1.35879e+01   1.27745e+01   1.39940e+01
| 4.46429e+00   1.46363e+01   1.36036e+01   1.53269e+01
| 4.54082e+00   1.56867e+01   1.44341e+01   1.66626e+01
| 4.61735e+00   1.67386e+01   1.52656e+01   1.80006e+01
| 4.69388e+00   1.77920e+01   1.60982e+01   1.93406e+01
| 4.77041e+00   1.88466e+01   1.69317e+01   2.06823e+01
| 4.84694e+00   1.99024e+01   1.77660e+01   2.20256e+01
| 4.92347e+00   2.09592e+01   1.86011e+01   2.33703e+01
| 5.00000e+00   2.20169e+01   1.94369e+01   2.47161e+01
[Pullup]
|Voltage   I (typ)   I (min)   I (max)
|Note, modeling breaks down at 250mA and above.  This is well beyond the functional   |
|operating range of the device.  Should this scenario occur, catastrophic failure and   |
|possible damage to the device and/or board is of higher concern than the I-V curve   |
|behavior.  The IBIS checker will flag currents in excess of 10A with warnings.  Lines   |
|with currents in excess of 0.35 A have been commented out.  The points still remain|
|available to the user if the user desires to use them.   |
|-2.50000e+00   2.19749e+01   1.80462e+01   2.68494e+01
|-2.42347e+00   2.09176e+01   1.72118e+01   2.55026e+01
|-2.34694e+00   1.98612e+01   1.63782e+01   2.41568e+01
|-2.27041e+00   1.88058e+01   1.55455e+01   2.28121e+01
|-2.19388e+00   1.77516e+01   1.47137e+01   2.14686e+01
|-2.11735e+00   1.66986e+01   1.38831e+01   2.01266e+01
|-2.04082e+00   1.56470e+01   1.30536e+01   1.87861e+01
|-1.96429e+00   1.45970e+01   1.22255e+01   1.74474e+01
|-1.88776e+00   1.35488e+01   1.13989e+01   1.61108e+01
|-1.81122e+00   1.25028e+01   1.05741e+01   1.47767e+01
|-1.73469e+00   1.14592e+01   9.75133e+00   1.34454e+01
|-1.65816e+00   1.04186e+01   8.93094e+00   1.21176e+01
|-1.58163e+00   9.38151e+00   8.11336e+00   1.07941e+01
|-1.50510e+00   8.34872e+00   7.29916e+00   9.47586e+00
|-1.42857e+00   7.32129e+00   6.48907e+00   8.16447e+00
|-1.35204e+00   6.30078e+00   5.68413e+00   6.86214e+00
|-1.27551e+00   5.28938e+00   4.88577e+00   5.57245e+00
|-1.19898e+00   4.29063e+00   4.09609e+00   4.30150e+00
|-1.12245e+00   3.31046e+00   3.31840e+00   3.06092e+00
|-1.04592e+00   2.35988e+00   2.55815e+00   1.87698e+00
|-9.69388e-01   1.46255e+00   1.82528e+00   8.26188e-01
|-8.92857e-01   6.79691e-01   1.14020e+00   1.77018e-01
|-8.16327e-01   1.78301e-01   5.50929e-01   7.20286e-02
-739.8mV  54.64mA    166.3mA    62.19mA
-663.3mV  40.61mA    45.96mA    55.4mA
-586.7mV  35.13mA    27.42mA    48.78mA
-204.1mV  11.53mA    8.292mA    16.47mA
255.1mV   -12.67mA   -8.857mA   -18.54mA
561.2mV   -24.84mA   -17.08mA   -36.7mA
943.9mV   -35.45mA   -23.78mA   -53.18mA
1.25V     -40.42mA   -26.48mA   -61.53mA
1.556V    -42.81mA   -27.59mA   -66.09mA
2.934V    -46.44mA   -31.28mA   -72.19mA
3.01V     -47.21mA   -40.39mA   -72.48mA
3.087V    -49.28mA   -106.7mA   -73.28mA
| 3.16327e+00   -5.35776e-02   -4.94236e-01   -7.58575e-02
| 3.23980e+00   -6.85824e-02   -1.43626e+00   -8.09810e-02
| 3.31633e+00   -2.12479e-01   -2.71822e+00   -8.81300e-02
| 3.39286e+00   -1.02359e+00   -4.15794e+00   -9.69441e-02
| 3.46939e+00   -2.55073e+00   -5.67974e+00   -1.18777e-01
| 3.54592e+00   -4.38708e+00   -7.25021e+00   -4.69271e-01
| 3.62245e+00   -6.35927e+00   -8.85247e+00   -2.14689e+00
| 3.69898e+00   -8.40369e+00   -1.04769e+01   -4.62063e+00
| 3.77551e+00   -1.04921e+01   -1.21177e+01   -7.36117e+00
| 3.85204e+00   -1.26099e+01   -1.37710e+01   -1.02197e+01
| 3.92857e+00   -1.47486e+01   -1.54342e+01   -1.31429e+01
| 4.00510e+00   -1.69029e+01   -1.71053e+01   -1.61066e+01
| 4.08163e+00   -1.90692e+01   -1.87829e+01   -1.90980e+01
| 4.15816e+00   -2.12452e+01   -2.04660e+01   -2.21093e+01
| 4.23469e+00   -2.34289e+01   -2.21537e+01   -2.51357e+01
| 4.31122e+00   -2.56192e+01   -2.38455e+01   -2.81738e+01
| 4.38776e+00   -2.78148e+01   -2.55407e+01   -3.12215e+01
| 4.46429e+00   -3.00151e+01   -2.72389e+01   -3.42769e+01
| 4.54082e+00   -3.22195e+01   -2.89399e+01   -3.73388e+01
| 4.61735e+00   -3.44273e+01   -3.06432e+01   -4.04061e+01
| 4.69388e+00   -3.66382e+01   -3.23486e+01   -4.34782e+01
| 4.77041e+00   -3.88519e+01   -3.40560e+01   -4.65543e+01
| 4.84694e+00   -4.10679e+01   -3.57652e+01   -4.96340e+01
| 4.92347e+00   -4.32862e+01   -3.74759e+01   -5.27168e+01
| 5.00000e+00   -4.55064e+01   -3.91880e+01   -5.58024e+01
[Ramp]
|   typ   min   max
dV/dt_r   0.936/0.951n   0.662/0.993n   1.168/0.848n
dV/dt_f   0.952/1.669n   0.676/2.324n   1.185/1.124n
R_load =   50
[Rising Waveform]
R_fixture = 50
V_fixture = 2.5   |Vcc_typ
V_fixture_min = 2.375 |Vcc_min
V_fixture_max = 2.625 |Vcc_max
C_fixture = 0.0p
| Time   typ   min   max
0s        939.3mV    1.271V     677.7mV
1.396ns   939.3mV    1.271V     700.7mV
1.774ns   939.3mV    1.271V     1.445V
2.109ns   996.6mV    1.271V     1.907V
2.59ns    1.705V     1.271V     2.391V
3.08ns    2.112V     1.288V     2.594V
4.013ns   2.456V     2.021V     2.623V
4.594ns   2.494V     2.22V      2.624V
5.317ns   2.498V     2.334V     2.624V
15ns      2.5V       2.375V     2.625V
[Falling Waveform]
R_fixture = 50
V_fixture = 2.5   |Vcc_typ
V_fixture_min = 2.375 |Vcc_min
V_fixture_max = 2.625 |Vcc_max
C_fixture = 0.0p
| Time   typ   min   max
0s        2.5V       2.375V     2.625V
2.105ns   2.514V     2.375V     2.601V
2.512ns   2.52V      2.375V     2.342V
3.046ns   2.498V     2.378V     1.789V
3.762ns   2.24V      2.392V     1.047V
4.518ns   1.777V     2.379V     772mV
5.507ns   1.25V      2.193V     701.8mV
6.849ns   1V         1.745V     679.1mV
9.345ns   940.1mV    1.334V     677.8mV
15ns      939.3mV    1.271V     677.7mV
[Rising Waveform]
R_fixture = 50
V_fixture = 0
C_fixture = 0.0p
| Time   typ   min   max
0s        1.586nV    7.942nV    136.6pV
2.164ns   -8.747mV   -21.31nV   25.48mV
2.616ns   -8.05mV    9.196uV    345.8mV
3.75ns    227.3mV    -7.979mV   1.617V
4.791ns   952.3mV    14.02mV    1.916V
5.409ns   1.301V     146.2mV    1.957V
6.262ns   1.52V      467.5mV    1.988V
7.456ns   1.62V      900.1mV    1.999V
8.75ns    1.654V     1.134V     1.999V
14.72ns   1.657V     1.272V     1.999V
[Falling Waveform]
R_fixture = 50
V_fixture = 0
C_fixture = 0.0p
| Time   typ   min   max
0s        1.657V     1.272V     1.999V
1.392ns   1.657V     1.272V     1.978V
2.014ns   1.648V     1.272V     826.3mV
2.246ns   1.357V     1.272V     516.6mV
2.642ns   760.2mV    1.272V     133.2mV
3.11ns    358.4mV    1.259V     12.68mV
3.673ns   85.01mV    671.3mV    1.391mV
4.058ns   24mV       377.1mV    854uV
5.215ns   1.106mV    44.06mV    520uV
15ns      38.04uV    65.97uV    21.88uV
